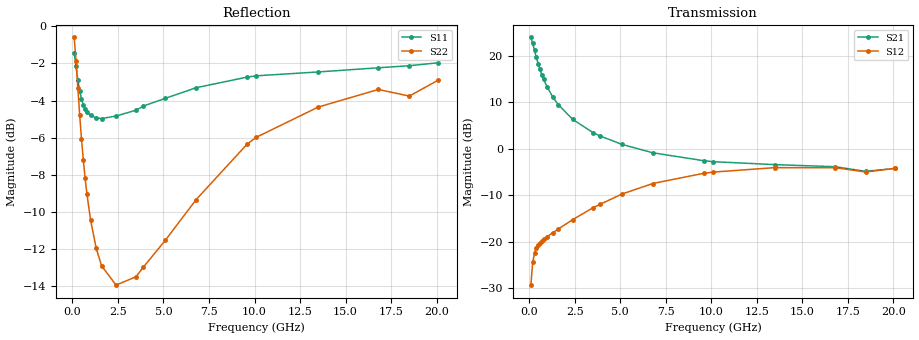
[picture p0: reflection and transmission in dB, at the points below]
!  Infineon Technologies AG
! BFR380L3 , PF131585-7, No.6, Th 09.10.01, soldered on pcb-board, measured with PP GSG850
!  Vce=1.0 V,  Ic=5.0 mA
! Common Emitter S-Parameters:  15. November 2001
#  GHz  S  MA  R  50
! f  S11  S21  S12  S22
! GHz  Mag  Ang  Mag  Ang  Mag  Ang  Mag  Ang
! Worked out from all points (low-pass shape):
!   201 points, 100 MHz to 20.1 GHz, reference 50 ohm
!   highest |S21| = 23.97 dB at 100 MHz (marker M1); lowest = -4.8 dB at 18.5 GHz (marker M2)
!   |S21| within 3 dB of the highest: start of sweep to 313.8 MHz
!   lowest |S11| = -5.0 dB at 1.6 GHz (marker M3), VSWR 3.59, Z = 13.9 - j1.52 ohm
!   |S11| at or under -10 dB: nowhere
!   |S22| runs from -13.9 to -0.6 dB; largest |S21 - S12| = 16
!   S11 on the Smith chart (normalised r, x): 100 MHz: 0.94, -3.08; 400 MHz: 0.32, -0.77; 1 GHz: 0.28, -0.22; 3.9 GHz: 0.27, +0.35; 9.6 GHz: 0.36, +1.12; 20.1 GHz: 0.95, +2.58
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0.1  0.8467 -33.3  15.8 158.8  0.03432 71.3  0.9332 -21.5
0.2  0.7793 -61.3  13.61 141.4  0.06015 59.7  0.8085 -39.0
0.3  0.7177 -84.0  11.45 128.4  0.07593 50.9  0.6815 -51.9
0.4  0.6687 -101.4  9.651 118.8  0.08605 45.4  0.5774 -61.5
0.5  0.6377 -115.0  8.241 111.4  0.09291 42.2  0.4978 -68.8
0.6  0.6143 -125.8  7.141 105.6  0.09845 40.5  0.4371 -74.6
0.7  0.5989 -134.6  6.29 100.8  0.1028 39.5  0.3898 -79.5
0.8  0.5863 -141.9  5.605 96.7  0.1066 39.2  0.353 -83.7
1  0.5754 -153.5  4.6 89.9  0.1141 39.3  0.3008 -90.6
1.3  0.5672 -166.3  3.621 81.7  0.1254 40.8  0.2535 -99.3
1.6  0.5644 -176.2  2.993 74.9  0.1374 42.7  0.2268 -106.7
2.4  0.5733 164.2  2.076 60.0  0.1737 45.9  0.2011 -123.6
3.5  0.5945 144.8  1.499 43.3  0.2322 46.8  0.2119 -143.0
3.9  0.6099 139.0  1.377 38.2  0.2534 46.2  0.2249 -150.7
5.1  0.6397 122.8  1.118 24.4  0.3272 41.6  0.2654 -169.3
6.8  0.6833 103.7  0.9078 9.8  0.4245 32.4  0.3418 165.4
9.6  0.7298 80.3  0.7458 -6.0  0.5465 14.0  0.482 133.2
10.1  0.7355 76.9  0.7287 -8.1  0.563 10.6  0.5026 127.9
13.5  0.7533 59.3  0.6774 -22.1  0.6288 -10.8  0.6061 97.6
16.8  0.773 47.1  0.6435 -33.4  0.628 -26.7  0.6758 75.9
18.5  0.783 45.1  0.573 -40.8  0.5642 -35.2  0.6487 70.3
20.1  0.7975 38.1  0.6175 -44.0  0.6177 -40.2  0.7166 59.6
